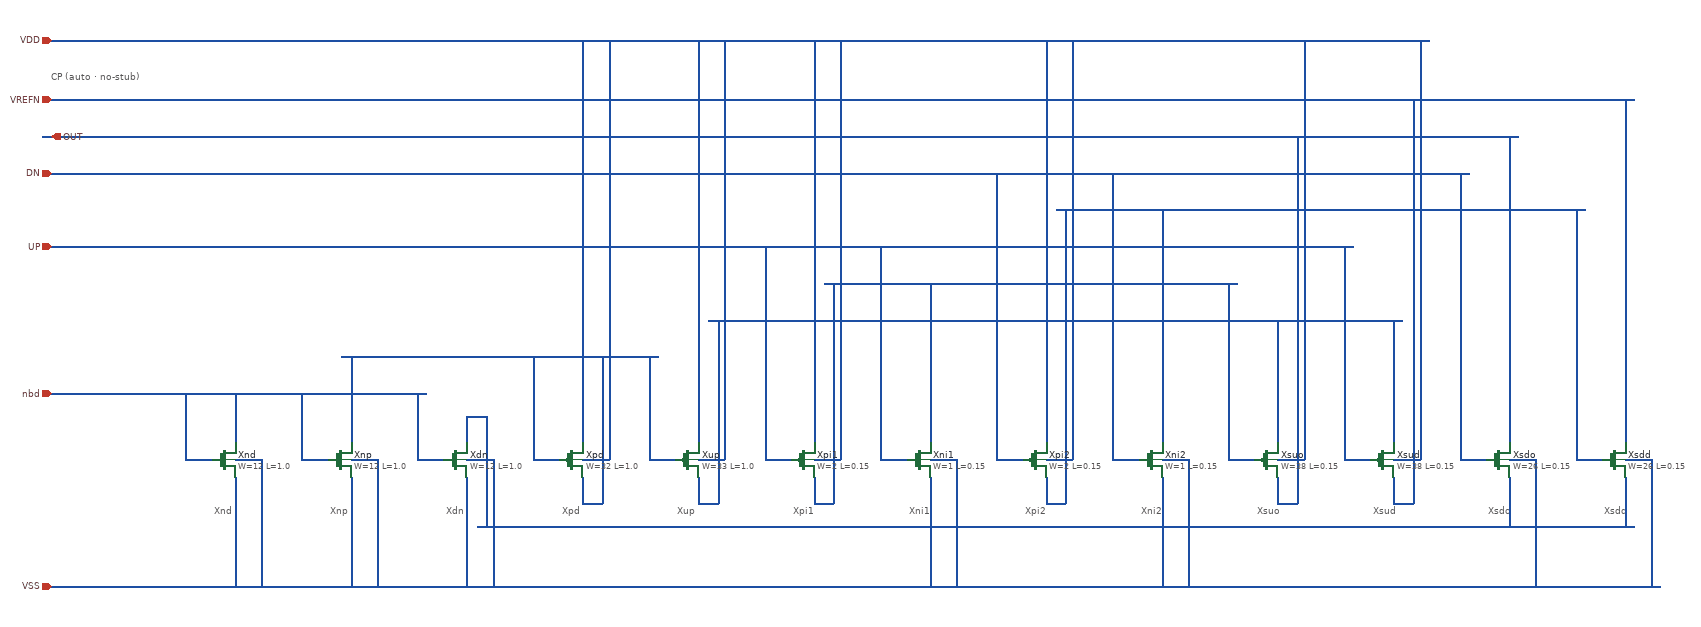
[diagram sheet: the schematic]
v {xschem version=3.4.6 file_version=1.2}
G {}
K {}
V {}
S {}
E {}
T {CP   (auto · no-stub)} -300 -680 0 0 0.4 0.4 {layer=4}
C {sky130_fd_pr/nfet_01v8.sym} 0 0 0 0 {name=Xnd
L=1.0
W=12
nf=1
model=nfet_01v8
spiceprefix=X}
N 20 -30 20 -76 {}
N -20 0 -66 0 {}
N 20 30 20 76 {}
N 20 0 66 0 {}
T {Xnd} -16 76 0 0 0.11 0.11 {layer=13}
C {sky130_fd_pr/nfet_01v8.sym} 202 0 0 0 {name=Xnp
L=1.0
W=12
nf=1
model=nfet_01v8
spiceprefix=X}
N 222 -30 222 -76 {}
N 182 0 136 0 {}
N 222 30 222 76 {}
N 222 0 268 0 {}
T {Xnp} 186 76 0 0 0.11 0.11 {layer=13}
C {sky130_fd_pr/nfet_01v8.sym} 404 0 0 0 {name=Xdn
L=1.0
W=12
nf=1
model=nfet_01v8
spiceprefix=X}
N 424 -30 424 -76 {}
N 384 0 338 0 {}
N 424 30 424 76 {}
N 424 0 470 0 {}
T {Xdn} 388 76 0 0 0.11 0.11 {layer=13}
C {sky130_fd_pr/pfet_01v8.sym} 606 0 0 0 {name=Xpd
L=1.0
W=32
nf=1
model=pfet_01v8
spiceprefix=X}
N 626 30 626 76 {}
N 586 0 540 0 {}
N 626 -30 626 -76 {}
N 626 0 672 0 {}
T {Xpd} 590 76 0 0 0.11 0.11 {layer=13}
C {sky130_fd_pr/pfet_01v8.sym} 808 0 0 0 {name=Xup
L=1.0
W=33
nf=1
model=pfet_01v8
spiceprefix=X}
N 828 30 828 76 {}
N 788 0 742 0 {}
N 828 -30 828 -76 {}
N 828 0 874 0 {}
T {Xup} 792 76 0 0 0.11 0.11 {layer=13}
C {sky130_fd_pr/pfet_01v8.sym} 1010 0 0 0 {name=Xpi1
L=0.15
W=2
nf=1
model=pfet_01v8
spiceprefix=X}
N 1030 30 1030 76 {}
N 990 0 944 0 {}
N 1030 -30 1030 -76 {}
N 1030 0 1076 0 {}
T {Xpi1} 994 76 0 0 0.11 0.11 {layer=13}
C {sky130_fd_pr/nfet_01v8.sym} 1212 0 0 0 {name=Xni1
L=0.15
W=1
nf=1
model=nfet_01v8
spiceprefix=X}
N 1232 -30 1232 -76 {}
N 1192 0 1146 0 {}
N 1232 30 1232 76 {}
N 1232 0 1278 0 {}
T {Xni1} 1196 76 0 0 0.11 0.11 {layer=13}
C {sky130_fd_pr/pfet_01v8.sym} 1414 0 0 0 {name=Xpi2
L=0.15
W=2
nf=1
model=pfet_01v8
spiceprefix=X}
N 1434 30 1434 76 {}
N 1394 0 1348 0 {}
N 1434 -30 1434 -76 {}
N 1434 0 1480 0 {}
T {Xpi2} 1398 76 0 0 0.11 0.11 {layer=13}
C {sky130_fd_pr/nfet_01v8.sym} 1616 0 0 0 {name=Xni2
L=0.15
W=1
nf=1
model=nfet_01v8
spiceprefix=X}
N 1636 -30 1636 -76 {}
N 1596 0 1550 0 {}
N 1636 30 1636 76 {}
N 1636 0 1682 0 {}
T {Xni2} 1600 76 0 0 0.11 0.11 {layer=13}
C {sky130_fd_pr/pfet_01v8.sym} 1818 0 0 0 {name=Xsuo
L=0.15
W=38
nf=1
model=pfet_01v8
spiceprefix=X}
N 1838 30 1838 76 {}
N 1798 0 1752 0 {}
N 1838 -30 1838 -76 {}
N 1838 0 1884 0 {}
T {Xsuo} 1802 76 0 0 0.11 0.11 {layer=13}
C {sky130_fd_pr/pfet_01v8.sym} 2020 0 0 0 {name=Xsud
L=0.15
W=38
nf=1
model=pfet_01v8
spiceprefix=X}
N 2040 30 2040 76 {}
N 2000 0 1954 0 {}
N 2040 -30 2040 -76 {}
N 2040 0 2086 0 {}
T {Xsud} 2004 76 0 0 0.11 0.11 {layer=13}
C {sky130_fd_pr/nfet_01v8.sym} 2222 0 0 0 {name=Xsdo
L=0.15
W=26
nf=1
model=nfet_01v8
spiceprefix=X}
N 2242 -30 2242 -76 {}
N 2202 0 2156 0 {}
N 2242 30 2242 76 {}
N 2242 0 2288 0 {}
T {Xsdo} 2206 76 0 0 0.11 0.11 {layer=13}
C {sky130_fd_pr/nfet_01v8.sym} 2424 0 0 0 {name=Xsdd
L=0.15
W=26
nf=1
model=nfet_01v8
spiceprefix=X}
N 2444 -30 2444 -76 {}
N 2404 0 2358 0 {}
N 2444 30 2444 76 {}
N 2444 0 2490 0 {}
T {Xsdd} 2408 76 0 0 0.11 0.11 {layer=13}
N 20 -76 20 -116 {}
N -66 0 -66 -116 {}
N 136 0 136 -116 {}
N 338 0 338 -116 {}
N 20 76 20 220 {}
N 66 0 66 220 {}
N 222 76 222 220 {}
N 268 0 268 220 {}
N 424 76 424 220 {}
N 470 0 470 220 {}
N 1232 76 1232 220 {}
N 1278 0 1278 220 {}
N 1636 76 1636 220 {}
N 1682 0 1682 220 {}
N 2288 0 2288 220 {}
N 2490 0 2490 220 {}
N 222 -76 222 -180 {}
N 540 0 540 -180 {}
N 742 0 742 -180 {}
N 2242 76 2242 116 {}
N 2444 76 2444 116 {}
N 626 -76 626 -732 {}
N 672 0 672 -732 {}
N 828 -76 828 -732 {}
N 874 0 874 -732 {}
N 1030 -76 1030 -732 {}
N 1076 0 1076 -732 {}
N 1434 -76 1434 -732 {}
N 1480 0 1480 -732 {}
N 1884 0 1884 -732 {}
N 2086 0 2086 -732 {}
N 1838 -76 1838 -244 {}
N 2040 -76 2040 -244 {}
N 1232 -76 1232 -308 {}
N 1752 0 1752 -308 {}
N 944 0 944 -372 {}
N 1146 0 1146 -372 {}
N 1954 0 1954 -372 {}
N 1636 -76 1636 -436 {}
N 2358 0 2358 -436 {}
N 1348 0 1348 -500 {}
N 1550 0 1550 -500 {}
N 2156 0 2156 -500 {}
N 2242 -76 2242 -564 {}
N 2444 -76 2444 -628 {}
N 626 76 660 76 {}
N 660 76 660 -180 {}
N 424 -76 458 -76 {}
N 458 -76 458 116 {}
N 828 76 862 76 {}
N 862 76 862 -244 {}
N 1030 76 1064 76 {}
N 1064 76 1064 -308 {}
N 1434 76 1468 76 {}
N 1468 76 1468 -436 {}
N 1838 76 1872 76 {}
N 1872 76 1872 -564 {}
N 2040 76 2074 76 {}
N 2074 76 2074 -628 {}
C {devices/ipin.sym} -300 -372 0 0 {name=ip1 lab=UP}
C {devices/ipin.sym} -300 -500 0 0 {name=ip2 lab=DN}
C {devices/opin.sym} -300 -564 0 0 {name=op3 lab=OUT}
C {devices/ipin.sym} -300 -628 0 0 {name=ip4 lab=VREFN}
C {devices/ipin.sym} -300 -732 0 0 {name=ip5 lab=VDD}
C {devices/ipin.sym} -300 -116 0 0 {name=ip6 lab=nbd}
C {devices/ipin.sym} -300 220 0 0 {name=ip7 lab=VSS}
N -316 -116 354 -116 {}
N -316 220 2506 220 {lab=VSS}
N 206 -180 758 -180 {}
N 442 116 2460 116 {}
N -316 -732 2102 -732 {lab=VDD}
N 846 -244 2056 -244 {}
N 1048 -308 1768 -308 {}
N -316 -372 1970 -372 {}
N 1452 -436 2374 -436 {}
N -316 -500 2172 -500 {}
N -316 -564 2258 -564 {}
N -316 -628 2460 -628 {}
